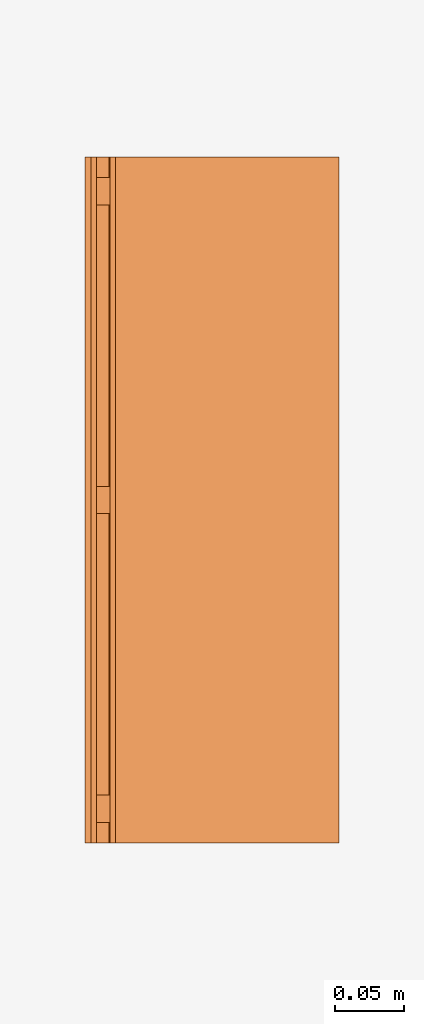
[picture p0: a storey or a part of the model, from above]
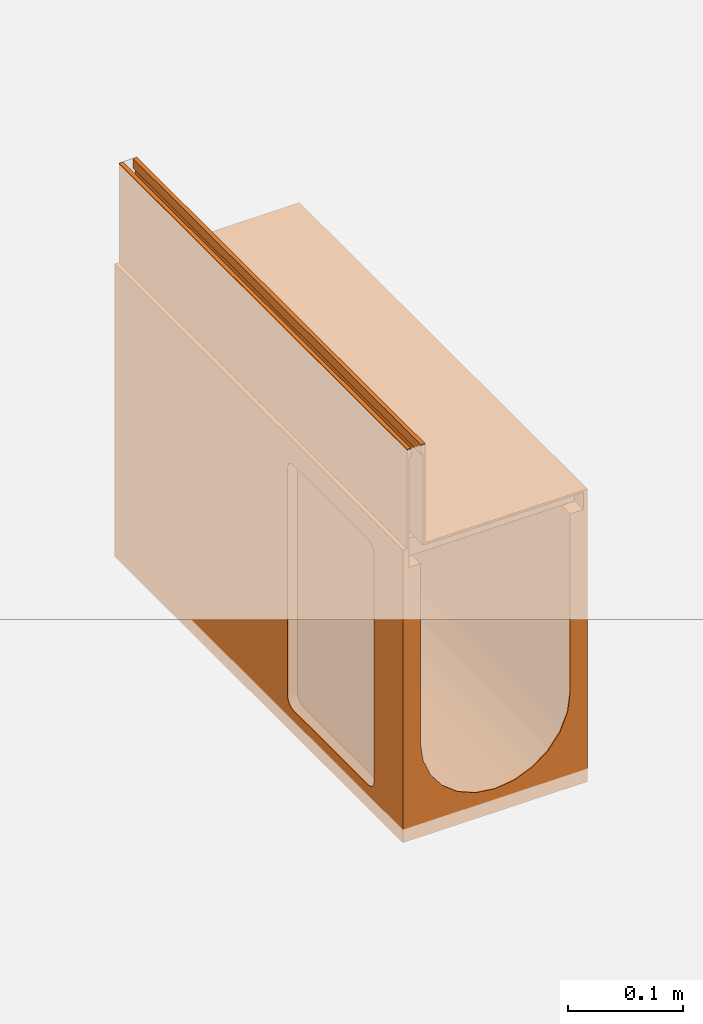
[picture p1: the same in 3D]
Properties of the parts of a building model (IFC2X3)

# File
Description: ViewDefinition [CoordinationView]
File name: 23155 - No 20.1 Constant Depth Channel - 500mm LG - Invert Depth 285mm.ifc
Time: 2013-10-30T12:25:01
Written by: Autodesk Revit 2013
Made in: 20120221_2030(x64)

# IfcProject, Project Number
LongName: Project Name; Phase: Project Status

# IfcSite, Default
RefLatitude: 42, 21, 30, 344238; RefLongitude: -71, -3, -35, -194702; RefElevation: 0 mm

# IfcBuilding
Pset_BuildingCommon - NumberOfStoreys: 1
Other - Client Name: Owner; Project Address: ## Street City, State Zip; Project Name: Project Name; Project Status: Project Status; Project Issue Date: Issue Date; Project Number: Project Number

# IfcBuildingStorey, Level 1
LongName: Level 1; Elevation: 0 mm
Constraints - Elevation Base: 0; Elevation: 0 mm
Graphics - Color: 0; Line Weight: 1; Symbol at End 1 Default: no; Line Pattern: Center; Symbol at End 2 Default: yes; Symbol: M_Level Head - Circle: M_Level Head - Circle
Identity Data - Structural: no; Name: Level 1; Building Story: yes
Dimensions - Computation Height: 0 mm

# IfcBuildingElementProxy: 23155 - No 20.1 Constant Depth Channel - 500mm LG - Invert Depth 285mm, Civil-Drainage-Channel-ACO-MultiDrain-M150D-Brickslot-Channel-System:23155 - No 20.1 Constant Depth Channel - 500mm LG - Invert Depth 285mm:23155 - No 20.1 Constant Depth Channel - 500mm LG - Invert Depth 285mm:196059
In: Level 1
Material: Steel, Galvanized, Vienite® Synthetic Resin Concrete
Phasing - Phase Created: New Construction
Dimensions - Brickslot Grating Void Depth: 0 mm; FloorCut_Length: -500 mm; EndCap Position: 500 mm; Brickslot Access Unit Void Depth: -6000 mm; Length: 1000 mm; Brickslot Access Unit Void Bottom Depth: -6105 mm; Brickslot Void Length: -500 mm; Custom_Void_Length: 0 mm; Volume: 7739628 mm3; End Cap Thickess: 3 mm; Depth: 310 mm; FloorCut_Width: 185 mm; EndCap_Height: -310 mm; FloorCut_Depth: 310 mm; InvDepth: 210 mm; Floor Cut Gap: 105 mm; FloorCut_HorPosition: 92.5 mm; Length Drain: -500 mm; Floor cut gap depth for access unit: 105 mm
Construction - 23177_Load Class C250 & D400_Brickslot_Access Unit_Galvanized Steel_500mm Long: no; 23159_Universal Endcap (Female End): no; 23176_Load Class C250 & D400_Brickslot Grating_Galvanized Steel_500mm Long: yes; 23175_Load Class C250 & D400_Brickslot Grating_Galvanized Steel_1000mm Long: no; 23159_Universal Endcap (Male End): no; 23157_Shallow Depth Channel with seal: no; Constant Depth Channel_500: yes; Constant Depth Channel_1000: no; Sump Unit: no; 23156_Shallow Depth Channel: no
Constraints - Moves With Nearby Elements: no; Level: Level: Level 1
Pset_BuildingElementProxyCommon - Reference: 23155 - No 20.1 Constant Depth Channel - 500mm LG - Invert Depth 285mm
Identity Data - Address: ACO Business Park, Hitchin Road, Shefford, Bedfordshire, United Kingdom SG17 5TE; Product Code: 23155; Model: ACO MultiDrain MD Brickslot - M150D; URL: www.aco.co.uk; Product Page URL: http://www.aco.co.uk/product_detail.php?id=58; Watermark 1: This file is the property of ACO Technologies PLC; Model Description: Channel drainage system; Telephone: +44 (0)1462 816666; Fax: +44 (0)1462 815895; Type Comments: ACO MultiDrain M150D 20.1J Constant Depth Channel 500mm Long; Assembly Description: Rain Water Drainage; Price: POA - contact ACO; Assembly Code: D2040; Watermarked By: www.aco.co.uk; Installation guidelines: http://www.aco.co.uk/download.php?id=173; e-mail Sales: customersupport@aco.co.uk; Product brochure: http://www.aco.co.uk/download.php?id=173; Watermark 2: This file is water marked and users are prohibited to reproduce, adapt, distribute this information; Manufacturer: ACO Technologies plc - ACO Water Management Division; Watermarked With: BIM Manager Premium Suite; Cost: 0; OmniClass Number: 23.70.50.24; OmniClass Title: Rainwater Removal; Maintenance guidelines: http://www.aco.co.uk/download.php?id=173; e-mail Technical: technical@aco.co.uk
General - TagNumber: 0; SerialNumber: 0
Model Properties - Brickslot Grating Product code 23175: N/A; End Cap Product code 23159: No. 306 Universal End Cap - 185mm wide x 310mm long - Spigot Ø110mm x 50mm long - Silver - Co-Polymer Polypropylene - 0.3kg; Brickslot Access Unit Product code 23177: Load Class C250/D400 - Brickslot Access Unit Galvanised steel - 500mm long x 105mm high - 10mm Slot -Intake area 10000mm²/m - 7.0kg; Brickslot Grating Product code 23176: Load Class C250/D400 -Brickslot Galvanized Steel - 500mm long x 105mm high - 10mm Slot - Intake area 10000mm²/m - 3.8kg
Data - Concrete Surround Volume - Load Class A 15 - Concrete Pavement: 0.11m³/m; Product Weight: 16.4Kg; Concrete Surround Volume - Load Class D 400 - Concrete Pavement: 0.25m³/m; Product Standard: BS EN 1433:2002, CE marked; Hydraulic Performance: http://www.aco.co.uk/download.php?id=173; Concrete Surround Volume - Load Class B 125 - C 250 - Concrete Pavement: 0.17m³/m; Channel C.S.A: 0.032m²; Load Class: A 15 - D 400; Product Dimensions: 500mm x 185mm x 310mm (LxWxH); Pre-formed Outlet Ø: N/A; Installation - Concrete Grade: Refer to brochure; ACO Hydraulic Design Software: http://www.acodesign.co.uk; Invert Depth: 285mm
Green Building Properties - Edge Rail Recycled Material Content: Between 40% - 90%; Edge Rail Recyclable: Fully recyclable; Channel Recyclable: Fully recyclable; Channel Recycled Material Content: 20% minimum
Materials and Finishes - Channel Material: Vienite® Synthetic Resin Concrete; Edge Rail Material: Steel; Edge Rail Colour: Silver; Edge Rail Finish: Pre-galvanised; Channel Colour: Brown
Other - Revision: 1; CreatedBy: www.aco.co.uk

# IfcOpeningElement: Opening (2)
In: Level 1
Constraints - Related to Mass: no; Room Bounding: yes; Height Offset From Level: 0 mm; Level: Level: Level 1
Dimensions - Thickness: 400 mm; Perimeter: 20000 mm; Area: 24991000 mm2; Volume: 9971767500 mm3
Structural - Structural: no; Enable Analytical Model: no
Phasing - Phase Created: New Construction
Analytical Properties - Roughness: 1; Heat Transfer Coefficient (U): 2.0925; Absorptance: 0.1; Thermal mass: 543920; Thermal Resistance (R): 0.477897
Graphics - Coarse Scale Fill Color: 0
Construction - Default Thickness: 400 mm; Function: 0
Materials and Finishes - Structural Material: Earth

# IfcSlab: Floor:Generic Floor - 400mm, Floor:Generic Floor - 400mm:193825
In: Level 1
PredefinedType: FLOOR; Material: Earth 400 mm
Constraints - Related to Mass: no; Room Bounding: yes; Height Offset From Level: 0 mm; Level: Level: Level 1
Dimensions - Thickness: 400 mm; Perimeter: 20000 mm; Area: 24991000 mm2; Volume: 9971767500 mm3
Structural - Structural: no; Enable Analytical Model: no
Phasing - Phase Created: New Construction
Pset_SlabCommon - Reference: Generic Floor - 400mm; IsExternal: no; LoadBearing: yes
Analytical Properties - Roughness: 1; Heat Transfer Coefficient (U): 2.0925; Absorptance: 0.1; Thermal mass: 543920; Thermal Resistance (R): 0.477897
Graphics - Coarse Scale Fill Color: 0
Construction - Default Thickness: 400 mm; Function: 0
Materials and Finishes - Structural Material: Earth
